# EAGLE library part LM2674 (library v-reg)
SWITCHING REGULATOR National Semiconductor

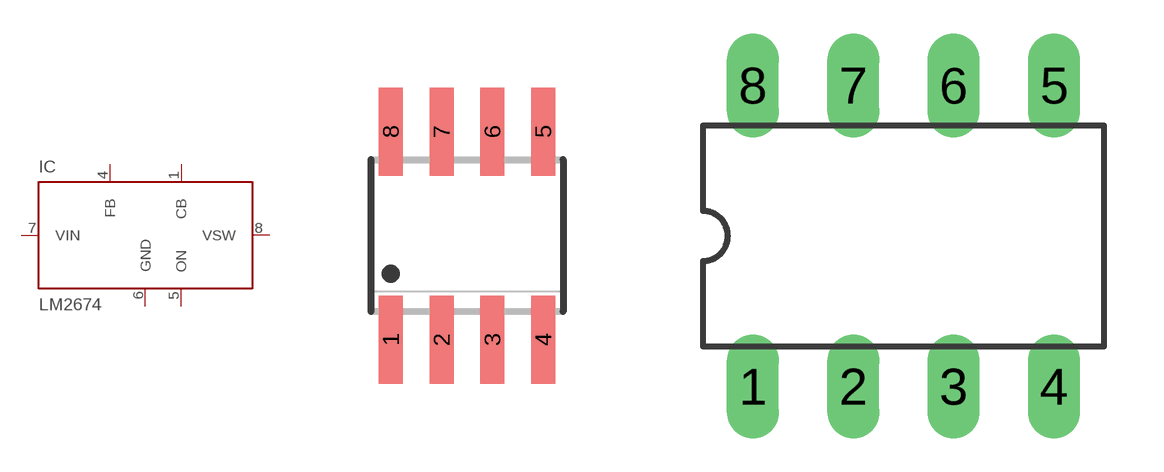
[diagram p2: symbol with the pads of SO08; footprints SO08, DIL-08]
Designator prefix IC

## LM2674M  [SO08]
1  CB  pas
4  FB  pas
5  ON  pas
6  GND  pas
7  VIN  pas
8  VSW  pas

## LM2674N  [DIL-08]
Pads as for SO08

## Footprint SO08 (pad centres in mm)
SMALL OUTLINE INTEGRATED CIRCUIT body 3.9 mm/JEDEC MS-012AA
smd 0.6 x 2.2: 1 -1.905,-2.6; 2 -0.635,-2.6; 3 0.635,-2.6; 4 1.905,-2.6; 5 1.905,2.6; 6 0.635,2.6; 7 -0.635,2.6; 8 -1.905,2.6

## Footprint DIL-08 (pad centres in mm)
drill 0.813 long: 1 -3.81,-3.81; 2 -1.27,-3.81; 3 1.27,-3.81; 4 3.81,-3.81; 5 3.81,3.81; 6 1.27,3.81; 7 -1.27,3.81; 8 -3.81,3.81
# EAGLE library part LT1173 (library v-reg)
LT1173 - Micropower DC/DC Converter Adjustable and Fixed 5V, 12V Operates at Supply Voltages From 2.0V to 30V Consumes Only 110&#181;A Supply Current Works in Step-Up or Step-Down Mode Only Three External Components Required Low Battery Detector Comparator On-Chip User-Adjustable Current Limit Internal 1A Power Switch Fixed or Adjustable Output Voltage Versions Space Saving 8-Pin MiniDIP or SO8 Package

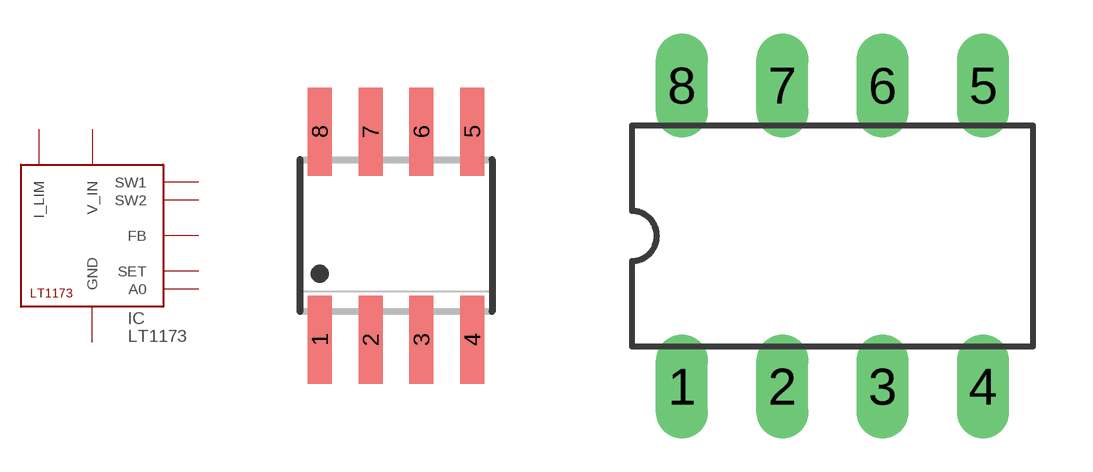
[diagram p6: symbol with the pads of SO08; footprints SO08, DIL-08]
Designator prefix IC

## LT1173CS8  [SO08]
1  I_LIM  pas
2  V_IN  pas
3  SW1  pas
4  SW2  pas
5  GND  pwr
6  A0  pas
7  SET  pas
8  FB  pas

## LT1173CN8  [DIL-08]
Pads as for SO08

## Footprint SO08 (pad centres in mm)
SMALL OUTLINE INTEGRATED CIRCUIT body 3.9 mm/JEDEC MS-012AA
smd 0.6 x 2.2: 1 -1.905,-2.6; 2 -0.635,-2.6; 3 0.635,-2.6; 4 1.905,-2.6; 5 1.905,2.6; 6 0.635,2.6; 7 -0.635,2.6; 8 -1.905,2.6

## Footprint DIL-08 (pad centres in mm)
drill 0.813 long: 1 -3.81,-3.81; 2 -1.27,-3.81; 3 1.27,-3.81; 4 3.81,-3.81; 5 3.81,3.81; 6 1.27,3.81; 7 -1.27,3.81; 8 -3.81,3.81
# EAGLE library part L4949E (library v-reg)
STMicroelectronics 5V 100mA low dropout voltage regulator Vin 5V to 28V (transients 40V), reset and comparator outputs, 200µA supply current

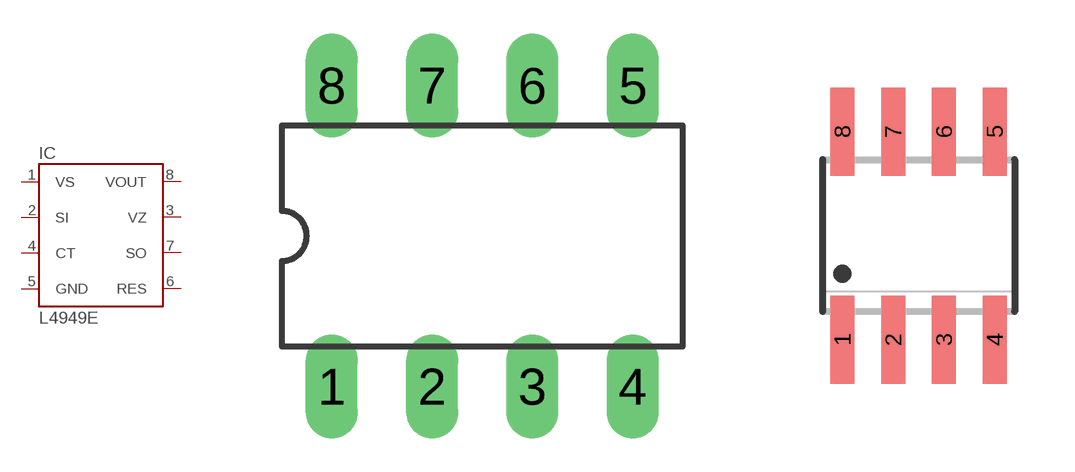
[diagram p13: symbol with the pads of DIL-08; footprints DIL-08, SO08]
Designator prefix IC

## L4949E  [DIL-08]
1  VS  pwr
2  SI  pas
3  VZ  out
4  CT  pas
5  GND  pwr
6  RES  out
7  SO  out
8  VOUT  out

## L4949ED  [SO08]
Pads as for DIL-08

## L4949EP  [SO20W]
1  VZ  out
2  CT  pas
10  RES  out
11  SO  out
12  VOUT  out
17  GND  pwr
19  VS  pwr
20  SI  pas

## Footprint DIL-08 (pad centres in mm)
drill 0.813 long: 1 -3.81,-3.81; 2 -1.27,-3.81; 3 1.27,-3.81; 4 3.81,-3.81; 5 3.81,3.81; 6 1.27,3.81; 7 -1.27,3.81; 8 -3.81,3.81

## Footprint SO08 (pad centres in mm)
SMALL OUTLINE INTEGRATED CIRCUIT body 3.9 mm/JEDEC MS-012AA
smd 0.6 x 2.2: 1 -1.905,-2.6; 2 -0.635,-2.6; 3 0.635,-2.6; 4 1.905,-2.6; 5 1.905,2.6; 6 0.635,2.6; 7 -0.635,2.6; 8 -1.905,2.6

## Footprint SO20W (pad centres in mm)
SMALL OUTLINE INTEGRATED CIRCUIT wide body 7.5 mm/JEDEC MS-013AC
smd 0.6 x 2.2: 1 -5.715,-4.6; 2 -4.445,-4.6; 3 -3.175,-4.6; 4 -1.905,-4.6; 5 -0.635,-4.6; 6 0.635,-4.6; 7 1.905,-4.6; 8 3.175,-4.6; 9 4.445,-4.6; 10 5.715,-4.6; 11 5.715,4.6; 12 4.445,4.6; 13 3.175,4.6; 14 1.905,4.6; 15 0.635,4.6; 16 -0.635,4.6; 17 -1.905,4.6; 18 -3.175,4.6; 19 -4.445,4.6; 20 -5.715,4.6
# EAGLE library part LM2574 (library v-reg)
National Semiconductor 0.5A "Simple Switcher"(c) 52kHz, Vout 1.23-37V (HV: 57V), Vin 40V (HV: 60V), 50µA standby current

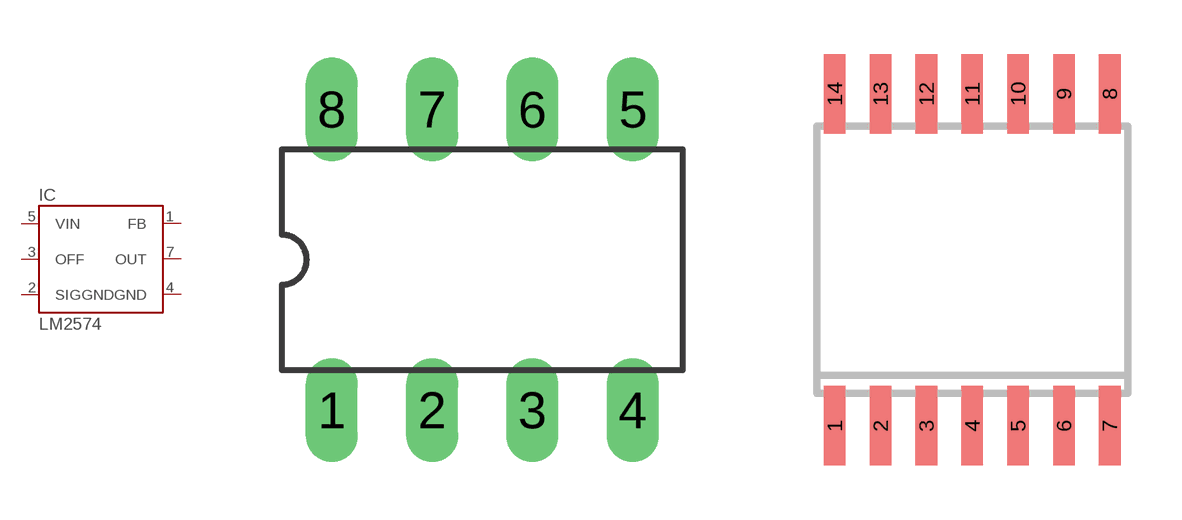
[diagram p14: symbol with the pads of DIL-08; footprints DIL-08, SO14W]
Designator prefix IC

## LM2574N  [DIL-08]
1  FB  in
2  SIGGND  pwr
3  OFF  in
4  GND  pwr
5  VIN  pwr
7  OUT  out

## LM2574M  [SO14W]
3  FB  in
4  SIGGND  pwr
5  OFF  in
6  GND  pwr
10  VIN  pwr
12  OUT  out

## Footprint DIL-08 (pad centres in mm)
drill 0.813 long: 1 -3.81,-3.81; 2 -1.27,-3.81; 3 1.27,-3.81; 4 3.81,-3.81; 5 3.81,3.81; 6 1.27,3.81; 7 -1.27,3.81; 8 -3.81,3.81

## Footprint SO14W (pad centres in mm)
SMALL OUTLINE INTEGRATED CIRCUIT wide body 7.5 mm
smd 0.6 x 2.2: 1 -3.81,-4.6; 2 -2.54,-4.6; 3 -1.27,-4.6; 4 0,-4.6; 5 1.27,-4.6; 6 2.54,-4.6; 7 3.81,-4.6; 8 3.81,4.6; 9 2.54,4.6; 10 1.27,4.6; 11 0,4.6; 12 -1.27,4.6; 13 -2.54,4.6; 14 -3.81,4.6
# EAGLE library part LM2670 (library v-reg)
National Semiconductor 3.0A "Simple Switcher"(c) 260kHz, Vout 1.2-37V, Vin 40V, 150mOhm DMOS switch, 50µA standby current, optional sync. to 280-400kHz

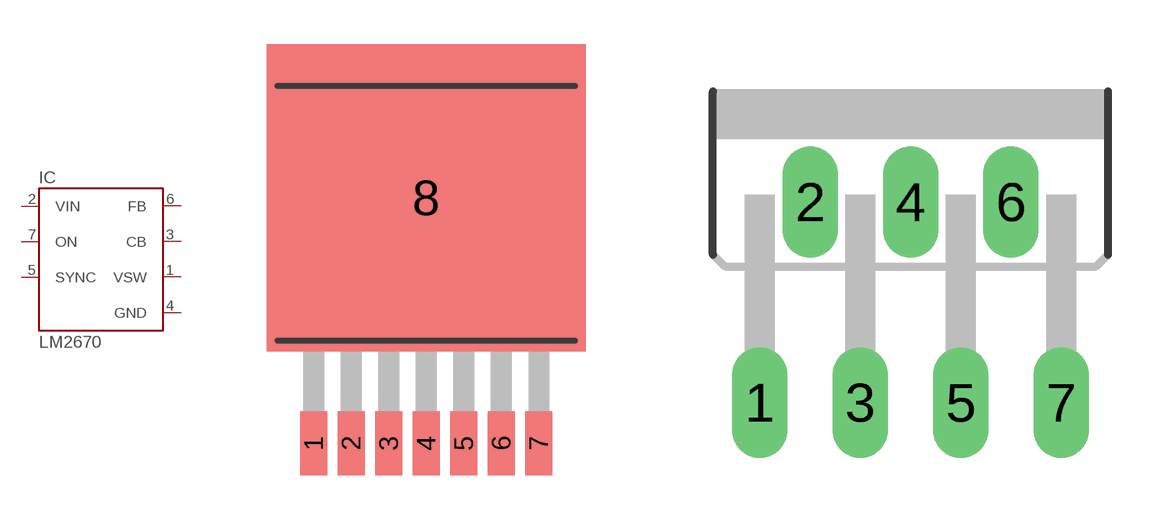
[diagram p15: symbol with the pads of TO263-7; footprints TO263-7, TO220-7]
Designator prefix IC

## LM2670S  [TO263-7]
1  VSW  out
2  VIN  pwr
3  CB  in
4  GND  pwr
5  SYNC  pas
6  FB  in
7  ON  pas

## LM2670T  [TO220-7]
Pads as for TO263-7

## Footprint TO263-7 (pad centres in mm)
TO-263, 7 pins and tab
smd 0.91 x 2.16: 1 -3.81,-5.78; 2 -2.54,-5.78; 3 -1.27,-5.78; 4 0,-5.78; 5 1.27,-5.78; 6 2.54,-5.78; 7 3.81,-5.78
smd 10.8 x 10.41: 8 0,2.54

## Footprint TO220-7 (pad centres in mm)
TO220-7
drill 0.9 long: 1 -3.81,-5.08; 2 -2.54,0; 3 -1.27,-5.08; 4 0,0; 5 1.27,-5.08; 6 2.54,0; 7 3.81,-5.08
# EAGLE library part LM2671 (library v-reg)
National Semiconductor 0.5A "Simple Switcher"(c) 260kHz, Vout 1.2-37V, Vin 40V, 250mOhm DMOS switch, 50µA standby current, optional sync. to 280-400kHz, soft start

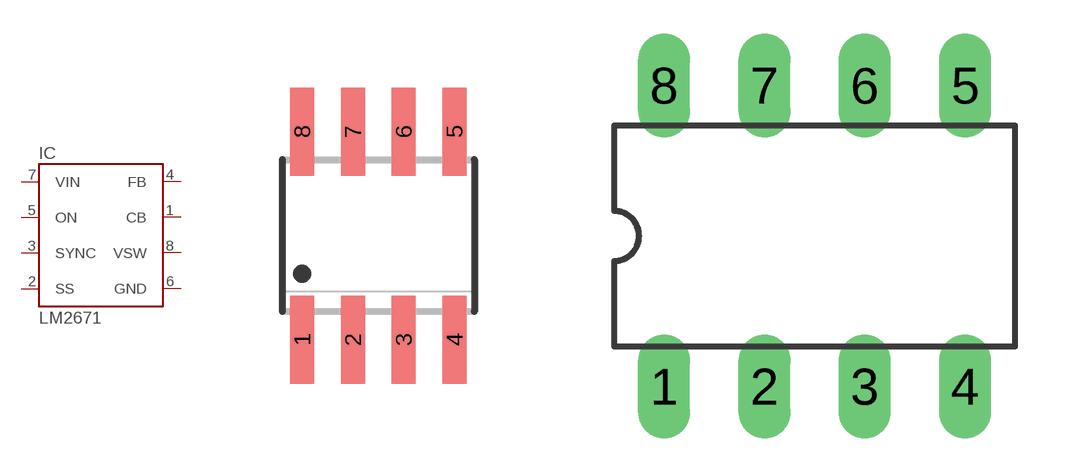
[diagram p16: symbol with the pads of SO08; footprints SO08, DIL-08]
Designator prefix IC

## LM2671M  [SO08]
1  CB  in
2  SS  pas
3  SYNC  pas
4  FB  in
5  ON  pas
6  GND  pwr
7  VIN  pwr
8  VSW  out

## LM2671N  [DIL-08]
Pads as for SO08

## Footprint SO08 (pad centres in mm)
SMALL OUTLINE INTEGRATED CIRCUIT body 3.9 mm/JEDEC MS-012AA
smd 0.6 x 2.2: 1 -1.905,-2.6; 2 -0.635,-2.6; 3 0.635,-2.6; 4 1.905,-2.6; 5 1.905,2.6; 6 0.635,2.6; 7 -0.635,2.6; 8 -1.905,2.6

## Footprint DIL-08 (pad centres in mm)
drill 0.813 long: 1 -3.81,-3.81; 2 -1.27,-3.81; 3 1.27,-3.81; 4 3.81,-3.81; 5 3.81,3.81; 6 1.27,3.81; 7 -1.27,3.81; 8 -3.81,3.81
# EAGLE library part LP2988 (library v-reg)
National Semiconductor Micropower Linear Regulator 200mA regulated output, Vin 16V max., ultra-low dropout of 180mV @ 200mA, 2µA standby current, error flag, programmable power-on delay, low noise

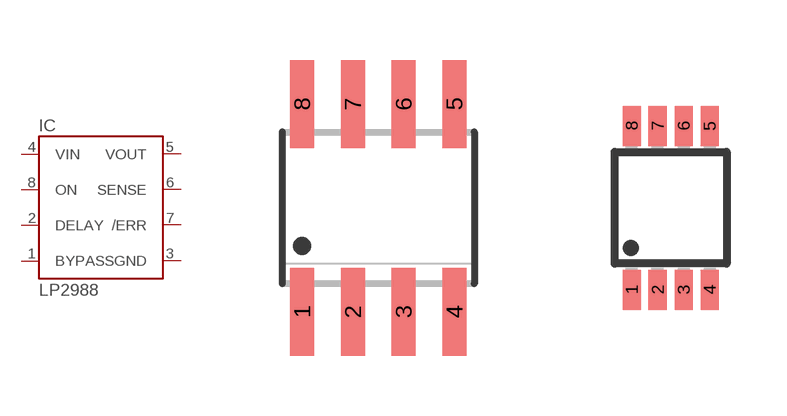
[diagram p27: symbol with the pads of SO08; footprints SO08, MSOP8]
Designator prefix IC

## LP2988M  [SO08]
1  BYPASS  pas
2  DELAY  pas
3  GND  pwr
4  VIN  pwr
5  VOUT  out
6  SENSE  in
7  /ERR  out
8  ON  in

## LP2988MM  [MSOP8]
Pads as for SO08

## Footprint SO08 (pad centres in mm)
SMALL OUTLINE INTEGRATED CIRCUIT body 3.9 mm/JEDEC MS-012AA
smd 0.6 x 2.2: 1 -1.905,-2.6; 2 -0.635,-2.6; 3 0.635,-2.6; 4 1.905,-2.6; 5 1.905,2.6; 6 0.635,2.6; 7 -0.635,2.6; 8 -1.905,2.6

## Footprint MSOP8 (pad centres in mm)
Micro Small Outline Package Grid .65mm
smd 0.45 x 1: 1 -0.975,-2.05; 2 -0.325,-2.05; 3 0.325,-2.05; 4 0.975,-2.05; 5 0.975,2.05; 6 0.325,2.05; 7 -0.325,2.05; 8 -0.975,2.05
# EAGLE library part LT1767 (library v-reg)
Linear Technology 1.5A step down switching regulator 1.25MHz, optional sync. up to 2MHz, Vin 3V to 25V, 6µA shutdown current

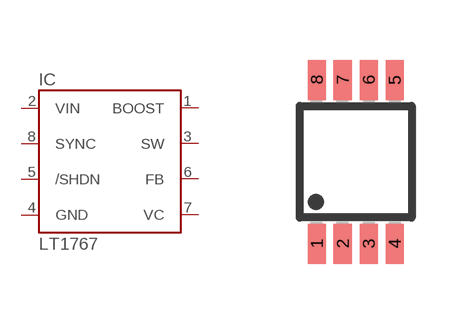
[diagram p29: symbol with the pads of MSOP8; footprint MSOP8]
Designator prefix IC

## LT1767M  [MSOP8]
1  BOOST  in
2  VIN  pwr
3  SW  out
4  GND  pwr
5  /SHDN  pas
6  FB  in
7  VC  in
8  SYNC  pas

## Footprint MSOP8 (pad centres in mm)
Micro Small Outline Package Grid .65mm
smd 0.45 x 1: 1 -0.975,-2.05; 2 -0.325,-2.05; 3 0.325,-2.05; 4 0.975,-2.05; 5 0.975,2.05; 6 0.325,2.05; 7 -0.325,2.05; 8 -0.975,2.05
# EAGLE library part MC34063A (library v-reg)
1.5A Step-Up/Down/Inverting Switching Regulator NPN Darlington Switch, Vin 3V to 40V, Current Limiter Input, adjustable Frequency up to 100kHz

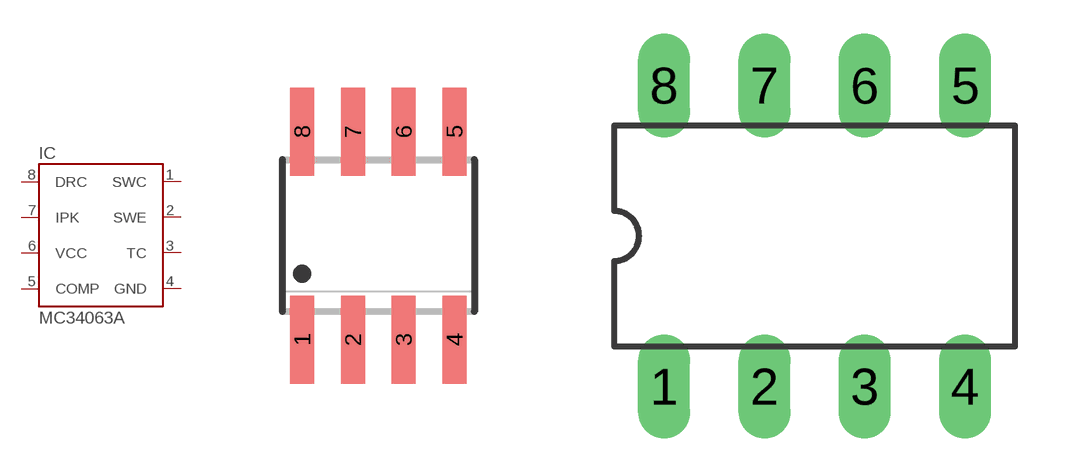
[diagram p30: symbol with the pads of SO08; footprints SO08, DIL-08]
Designator prefix IC

## MC34063AD  [SO08]
1  SWC
2  SWE
3  TC  pas
4  GND  pwr
5  COMP  in
6  VCC  pwr
7  IPK  in
8  DRC  in

## MC34063AP  [DIL-08]
Pads as for SO08

## Footprint SO08 (pad centres in mm)
SMALL OUTLINE INTEGRATED CIRCUIT body 3.9 mm/JEDEC MS-012AA
smd 0.6 x 2.2: 1 -1.905,-2.6; 2 -0.635,-2.6; 3 0.635,-2.6; 4 1.905,-2.6; 5 1.905,2.6; 6 0.635,2.6; 7 -0.635,2.6; 8 -1.905,2.6

## Footprint DIL-08 (pad centres in mm)
drill 0.813 long: 1 -3.81,-3.81; 2 -1.27,-3.81; 3 1.27,-3.81; 4 3.81,-3.81; 5 3.81,3.81; 6 1.27,3.81; 7 -1.27,3.81; 8 -3.81,3.81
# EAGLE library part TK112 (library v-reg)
Ultra low dropout positive regulator, 300mA, enable input

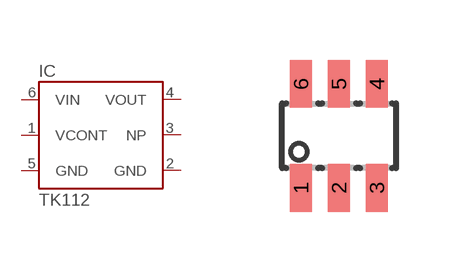
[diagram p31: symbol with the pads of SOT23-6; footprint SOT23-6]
Designator prefix IC

## TK112CM  [SOT23-6]
1  VCONT  in
2  GND  pwr
3  NP  pas
4  VOUT  out
5  GND  pwr
6  VIN  pwr

## Footprint SOT23-6 (pad centres in mm)
smd 0.55 x 1.2: 1 -0.95,-1.3; 2 0,-1.3; 3 0.95,-1.3; 4 0.95,1.3; 5 0,1.3; 6 -0.95,1.3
